VERSION 5.7 ;
  NOWIREEXTENSIONATPIN ON ;
  DIVIDERCHAR "/" ;
  BUSBITCHARS "[]" ;
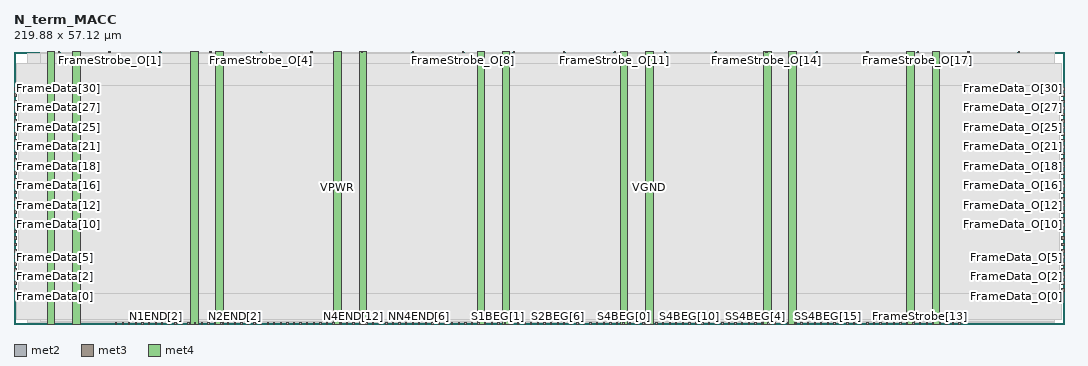
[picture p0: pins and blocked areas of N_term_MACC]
MACRO N_term_MACC
  CLASS BLOCK ;
  FOREIGN N_term_MACC ;
  ORIGIN 0.000 0.000 ;
  SIZE 219.880 BY 57.120 ;
  PIN CI
    DIRECTION INPUT ;
    USE SIGNAL ;
    PORT
      LAYER met2 ;
        RECT 98.530 0.000 98.810 0.280 ;
    END
  END CI
  PIN FrameData[0]
    DIRECTION INPUT ;
    USE SIGNAL ;
    ANTENNAGATEAREA 0.593700 ;
    ANTENNADIFFAREA 0.434700 ;
    PORT
      LAYER met3 ;
        RECT 0.000 6.840 0.600 7.440 ;
    END
  END FrameData[0]
  PIN FrameData[10]
    DIRECTION INPUT ;
    USE SIGNAL ;
    ANTENNAGATEAREA 0.593700 ;
    ANTENNADIFFAREA 0.434700 ;
    PORT
      LAYER met3 ;
        RECT 0.000 20.440 0.600 21.040 ;
    END
  END FrameData[10]
  PIN FrameData[11]
    DIRECTION INPUT ;
    USE SIGNAL ;
    ANTENNAGATEAREA 0.593700 ;
    ANTENNADIFFAREA 0.434700 ;
    PORT
      LAYER met3 ;
        RECT 0.000 21.800 0.600 22.400 ;
    END
  END FrameData[11]
  PIN FrameData[12]
    DIRECTION INPUT ;
    USE SIGNAL ;
    ANTENNAGATEAREA 0.159000 ;
    PORT
      LAYER met3 ;
        RECT 0.000 23.160 0.600 23.760 ;
    END
  END FrameData[12]
  PIN FrameData[13]
    DIRECTION INPUT ;
    USE SIGNAL ;
    ANTENNAGATEAREA 0.593700 ;
    ANTENNADIFFAREA 0.434700 ;
    PORT
      LAYER met3 ;
        RECT 0.000 24.520 0.600 25.120 ;
    END
  END FrameData[13]
  PIN FrameData[14]
    DIRECTION INPUT ;
    USE SIGNAL ;
    ANTENNAGATEAREA 0.593700 ;
    ANTENNADIFFAREA 0.434700 ;
    PORT
      LAYER met3 ;
        RECT 0.000 25.880 0.600 26.480 ;
    END
  END FrameData[14]
  PIN FrameData[15]
    DIRECTION INPUT ;
    USE SIGNAL ;
    ANTENNAGATEAREA 0.593700 ;
    ANTENNADIFFAREA 0.434700 ;
    PORT
      LAYER met3 ;
        RECT 0.000 27.240 0.600 27.840 ;
    END
  END FrameData[15]
  PIN FrameData[16]
    DIRECTION INPUT ;
    USE SIGNAL ;
    ANTENNAGATEAREA 0.593700 ;
    ANTENNADIFFAREA 0.434700 ;
    PORT
      LAYER met3 ;
        RECT 0.000 28.600 0.600 29.200 ;
    END
  END FrameData[16]
  PIN FrameData[17]
    DIRECTION INPUT ;
    USE SIGNAL ;
    ANTENNAGATEAREA 0.593700 ;
    ANTENNADIFFAREA 0.434700 ;
    PORT
      LAYER met3 ;
        RECT 0.000 29.960 0.600 30.560 ;
    END
  END FrameData[17]
  PIN FrameData[18]
    DIRECTION INPUT ;
    USE SIGNAL ;
    ANTENNAGATEAREA 0.593700 ;
    ANTENNADIFFAREA 0.434700 ;
    PORT
      LAYER met3 ;
        RECT 0.000 31.320 0.600 31.920 ;
    END
  END FrameData[18]
  PIN FrameData[19]
    DIRECTION INPUT ;
    USE SIGNAL ;
    ANTENNAGATEAREA 0.593700 ;
    ANTENNADIFFAREA 0.434700 ;
    PORT
      LAYER met3 ;
        RECT 0.000 32.680 0.600 33.280 ;
    END
  END FrameData[19]
  PIN FrameData[1]
    DIRECTION INPUT ;
    USE SIGNAL ;
    ANTENNAGATEAREA 0.159000 ;
    PORT
      LAYER met3 ;
        RECT 0.000 8.200 0.600 8.800 ;
    END
  END FrameData[1]
  PIN FrameData[20]
    DIRECTION INPUT ;
    USE SIGNAL ;
    ANTENNAGATEAREA 0.593700 ;
    ANTENNADIFFAREA 0.434700 ;
    PORT
      LAYER met3 ;
        RECT 0.000 34.040 0.600 34.640 ;
    END
  END FrameData[20]
  PIN FrameData[21]
    DIRECTION INPUT ;
    USE SIGNAL ;
    ANTENNAGATEAREA 0.593700 ;
    ANTENNADIFFAREA 0.434700 ;
    PORT
      LAYER met3 ;
        RECT 0.000 35.400 0.600 36.000 ;
    END
  END FrameData[21]
  PIN FrameData[22]
    DIRECTION INPUT ;
    USE SIGNAL ;
    ANTENNAGATEAREA 0.159000 ;
    PORT
      LAYER met3 ;
        RECT 0.000 36.760 0.600 37.360 ;
    END
  END FrameData[22]
  PIN FrameData[23]
    DIRECTION INPUT ;
    USE SIGNAL ;
    ANTENNAGATEAREA 0.593700 ;
    ANTENNADIFFAREA 0.434700 ;
    PORT
      LAYER met3 ;
        RECT 0.000 38.120 0.600 38.720 ;
    END
  END FrameData[23]
  PIN FrameData[24]
    DIRECTION INPUT ;
    USE SIGNAL ;
    ANTENNAGATEAREA 0.593700 ;
    ANTENNADIFFAREA 0.434700 ;
    PORT
      LAYER met3 ;
        RECT 0.000 39.480 0.600 40.080 ;
    END
  END FrameData[24]
  PIN FrameData[25]
    DIRECTION INPUT ;
    USE SIGNAL ;
    ANTENNAGATEAREA 0.593700 ;
    ANTENNADIFFAREA 0.434700 ;
    PORT
      LAYER met3 ;
        RECT 0.000 40.840 0.600 41.440 ;
    END
  END FrameData[25]
  PIN FrameData[26]
    DIRECTION INPUT ;
    USE SIGNAL ;
    ANTENNAGATEAREA 0.593700 ;
    ANTENNADIFFAREA 0.434700 ;
    PORT
      LAYER met3 ;
        RECT 0.000 42.200 0.600 42.800 ;
    END
  END FrameData[26]
  PIN FrameData[27]
    DIRECTION INPUT ;
    USE SIGNAL ;
    ANTENNAGATEAREA 0.593700 ;
    ANTENNADIFFAREA 0.434700 ;
    PORT
      LAYER met3 ;
        RECT 0.000 43.560 0.600 44.160 ;
    END
  END FrameData[27]
  PIN FrameData[28]
    DIRECTION INPUT ;
    USE SIGNAL ;
    ANTENNAGATEAREA 0.593700 ;
    ANTENNADIFFAREA 0.434700 ;
    PORT
      LAYER met3 ;
        RECT 0.000 44.920 0.600 45.520 ;
    END
  END FrameData[28]
  PIN FrameData[29]
    DIRECTION INPUT ;
    USE SIGNAL ;
    ANTENNAGATEAREA 0.593700 ;
    ANTENNADIFFAREA 0.434700 ;
    PORT
      LAYER met3 ;
        RECT 0.000 46.280 0.600 46.880 ;
    END
  END FrameData[29]
  PIN FrameData[2]
    DIRECTION INPUT ;
    USE SIGNAL ;
    ANTENNAGATEAREA 0.593700 ;
    ANTENNADIFFAREA 0.434700 ;
    PORT
      LAYER met3 ;
        RECT 0.000 9.560 0.600 10.160 ;
    END
  END FrameData[2]
  PIN FrameData[30]
    DIRECTION INPUT ;
    USE SIGNAL ;
    ANTENNAGATEAREA 0.593700 ;
    ANTENNADIFFAREA 0.434700 ;
    PORT
      LAYER met3 ;
        RECT 0.000 47.640 0.600 48.240 ;
    END
  END FrameData[30]
  PIN FrameData[31]
    DIRECTION INPUT ;
    USE SIGNAL ;
    ANTENNAGATEAREA 0.593700 ;
    ANTENNADIFFAREA 0.434700 ;
    PORT
      LAYER met3 ;
        RECT 0.000 49.000 0.600 49.600 ;
    END
  END FrameData[31]
  PIN FrameData[3]
    DIRECTION INPUT ;
    USE SIGNAL ;
    ANTENNAGATEAREA 0.593700 ;
    ANTENNADIFFAREA 0.434700 ;
    PORT
      LAYER met3 ;
        RECT 0.000 10.920 0.600 11.520 ;
    END
  END FrameData[3]
  PIN FrameData[4]
    DIRECTION INPUT ;
    USE SIGNAL ;
    ANTENNAGATEAREA 0.593700 ;
    ANTENNADIFFAREA 0.434700 ;
    PORT
      LAYER met3 ;
        RECT 0.000 12.280 0.600 12.880 ;
    END
  END FrameData[4]
  PIN FrameData[5]
    DIRECTION INPUT ;
    USE SIGNAL ;
    ANTENNAGATEAREA 0.593700 ;
    ANTENNADIFFAREA 0.434700 ;
    PORT
      LAYER met3 ;
        RECT 0.000 13.640 0.600 14.240 ;
    END
  END FrameData[5]
  PIN FrameData[6]
    DIRECTION INPUT ;
    USE SIGNAL ;
    ANTENNAGATEAREA 0.593700 ;
    ANTENNADIFFAREA 0.434700 ;
    PORT
      LAYER met3 ;
        RECT 0.000 15.000 0.600 15.600 ;
    END
  END FrameData[6]
  PIN FrameData[7]
    DIRECTION INPUT ;
    USE SIGNAL ;
    ANTENNAGATEAREA 0.593700 ;
    ANTENNADIFFAREA 0.434700 ;
    PORT
      LAYER met3 ;
        RECT 0.000 16.360 0.600 16.960 ;
    END
  END FrameData[7]
  PIN FrameData[8]
    DIRECTION INPUT ;
    USE SIGNAL ;
    ANTENNAGATEAREA 0.593700 ;
    ANTENNADIFFAREA 0.434700 ;
    PORT
      LAYER met3 ;
        RECT 0.000 17.720 0.600 18.320 ;
    END
  END FrameData[8]
  PIN FrameData[9]
    DIRECTION INPUT ;
    USE SIGNAL ;
    ANTENNAGATEAREA 0.593700 ;
    ANTENNADIFFAREA 0.434700 ;
    PORT
      LAYER met3 ;
        RECT 0.000 19.080 0.600 19.680 ;
    END
  END FrameData[9]
  PIN FrameData_O[0]
    DIRECTION OUTPUT ;
    USE SIGNAL ;
    ANTENNADIFFAREA 0.702900 ;
    PORT
      LAYER met3 ;
        RECT 219.280 6.840 219.880 7.440 ;
    END
  END FrameData_O[0]
  PIN FrameData_O[10]
    DIRECTION OUTPUT ;
    USE SIGNAL ;
    ANTENNADIFFAREA 0.702900 ;
    PORT
      LAYER met3 ;
        RECT 219.280 20.440 219.880 21.040 ;
    END
  END FrameData_O[10]
  PIN FrameData_O[11]
    DIRECTION OUTPUT ;
    USE SIGNAL ;
    ANTENNADIFFAREA 0.702900 ;
    PORT
      LAYER met3 ;
        RECT 219.280 21.800 219.880 22.400 ;
    END
  END FrameData_O[11]
  PIN FrameData_O[12]
    DIRECTION OUTPUT ;
    USE SIGNAL ;
    ANTENNADIFFAREA 0.702900 ;
    PORT
      LAYER met3 ;
        RECT 219.280 23.160 219.880 23.760 ;
    END
  END FrameData_O[12]
  PIN FrameData_O[13]
    DIRECTION OUTPUT ;
    USE SIGNAL ;
    ANTENNADIFFAREA 0.702900 ;
    PORT
      LAYER met3 ;
        RECT 219.280 24.520 219.880 25.120 ;
    END
  END FrameData_O[13]
  PIN FrameData_O[14]
    DIRECTION OUTPUT ;
    USE SIGNAL ;
    ANTENNADIFFAREA 0.702900 ;
    PORT
      LAYER met3 ;
        RECT 219.280 25.880 219.880 26.480 ;
    END
  END FrameData_O[14]
  PIN FrameData_O[15]
    DIRECTION OUTPUT ;
    USE SIGNAL ;
    ANTENNADIFFAREA 0.702900 ;
    PORT
      LAYER met3 ;
        RECT 219.280 27.240 219.880 27.840 ;
    END
  END FrameData_O[15]
  PIN FrameData_O[16]
    DIRECTION OUTPUT ;
    USE SIGNAL ;
    ANTENNADIFFAREA 0.702900 ;
    PORT
      LAYER met3 ;
        RECT 219.280 28.600 219.880 29.200 ;
    END
  END FrameData_O[16]
  PIN FrameData_O[17]
    DIRECTION OUTPUT ;
    USE SIGNAL ;
    ANTENNADIFFAREA 0.702900 ;
    PORT
      LAYER met3 ;
        RECT 219.280 29.960 219.880 30.560 ;
    END
  END FrameData_O[17]
  PIN FrameData_O[18]
    DIRECTION OUTPUT ;
    USE SIGNAL ;
    ANTENNADIFFAREA 0.702900 ;
    PORT
      LAYER met3 ;
        RECT 219.280 31.320 219.880 31.920 ;
    END
  END FrameData_O[18]
  PIN FrameData_O[19]
    DIRECTION OUTPUT ;
    USE SIGNAL ;
    ANTENNADIFFAREA 0.702900 ;
    PORT
      LAYER met3 ;
        RECT 219.280 32.680 219.880 33.280 ;
    END
  END FrameData_O[19]
  PIN FrameData_O[1]
    DIRECTION OUTPUT ;
    USE SIGNAL ;
    ANTENNADIFFAREA 0.702900 ;
    PORT
      LAYER met3 ;
        RECT 219.280 8.200 219.880 8.800 ;
    END
  END FrameData_O[1]
  PIN FrameData_O[20]
    DIRECTION OUTPUT ;
    USE SIGNAL ;
    ANTENNADIFFAREA 0.702900 ;
    PORT
      LAYER met3 ;
        RECT 219.280 34.040 219.880 34.640 ;
    END
  END FrameData_O[20]
  PIN FrameData_O[21]
    DIRECTION OUTPUT ;
    USE SIGNAL ;
    ANTENNADIFFAREA 0.702900 ;
    PORT
      LAYER met3 ;
        RECT 219.280 35.400 219.880 36.000 ;
    END
  END FrameData_O[21]
  PIN FrameData_O[22]
    DIRECTION OUTPUT ;
    USE SIGNAL ;
    ANTENNADIFFAREA 0.702900 ;
    PORT
      LAYER met3 ;
        RECT 219.280 36.760 219.880 37.360 ;
    END
  END FrameData_O[22]
  PIN FrameData_O[23]
    DIRECTION OUTPUT ;
    USE SIGNAL ;
    ANTENNADIFFAREA 0.702900 ;
    PORT
      LAYER met3 ;
        RECT 219.280 38.120 219.880 38.720 ;
    END
  END FrameData_O[23]
  PIN FrameData_O[24]
    DIRECTION OUTPUT ;
    USE SIGNAL ;
    ANTENNADIFFAREA 0.702900 ;
    PORT
      LAYER met3 ;
        RECT 219.280 39.480 219.880 40.080 ;
    END
  END FrameData_O[24]
  PIN FrameData_O[25]
    DIRECTION OUTPUT ;
    USE SIGNAL ;
    ANTENNADIFFAREA 0.702900 ;
    PORT
      LAYER met3 ;
        RECT 219.280 40.840 219.880 41.440 ;
    END
  END FrameData_O[25]
  PIN FrameData_O[26]
    DIRECTION OUTPUT ;
    USE SIGNAL ;
    ANTENNADIFFAREA 0.702900 ;
    PORT
      LAYER met3 ;
        RECT 219.280 42.200 219.880 42.800 ;
    END
  END FrameData_O[26]
  PIN FrameData_O[27]
    DIRECTION OUTPUT ;
    USE SIGNAL ;
    ANTENNADIFFAREA 0.702900 ;
    PORT
      LAYER met3 ;
        RECT 219.280 43.560 219.880 44.160 ;
    END
  END FrameData_O[27]
  PIN FrameData_O[28]
    DIRECTION OUTPUT ;
    USE SIGNAL ;
    ANTENNADIFFAREA 0.702900 ;
    PORT
      LAYER met3 ;
        RECT 219.280 44.920 219.880 45.520 ;
    END
  END FrameData_O[28]
  PIN FrameData_O[29]
    DIRECTION OUTPUT ;
    USE SIGNAL ;
    ANTENNADIFFAREA 0.702900 ;
    PORT
      LAYER met3 ;
        RECT 219.280 46.280 219.880 46.880 ;
    END
  END FrameData_O[29]
  PIN FrameData_O[2]
    DIRECTION OUTPUT ;
    USE SIGNAL ;
    ANTENNADIFFAREA 0.702900 ;
    PORT
      LAYER met3 ;
        RECT 219.280 9.560 219.880 10.160 ;
    END
  END FrameData_O[2]
  PIN FrameData_O[30]
    DIRECTION OUTPUT ;
    USE SIGNAL ;
    ANTENNADIFFAREA 0.702900 ;
    PORT
      LAYER met3 ;
        RECT 219.280 47.640 219.880 48.240 ;
    END
  END FrameData_O[30]
  PIN FrameData_O[31]
    DIRECTION OUTPUT ;
    USE SIGNAL ;
    ANTENNADIFFAREA 0.702900 ;
    PORT
      LAYER met3 ;
        RECT 219.280 49.000 219.880 49.600 ;
    END
  END FrameData_O[31]
  PIN FrameData_O[3]
    DIRECTION OUTPUT ;
    USE SIGNAL ;
    ANTENNADIFFAREA 0.702900 ;
    PORT
      LAYER met3 ;
        RECT 219.280 10.920 219.880 11.520 ;
    END
  END FrameData_O[3]
  PIN FrameData_O[4]
    DIRECTION OUTPUT ;
    USE SIGNAL ;
    ANTENNADIFFAREA 0.702900 ;
    PORT
      LAYER met3 ;
        RECT 219.280 12.280 219.880 12.880 ;
    END
  END FrameData_O[4]
  PIN FrameData_O[5]
    DIRECTION OUTPUT ;
    USE SIGNAL ;
    ANTENNADIFFAREA 0.702900 ;
    PORT
      LAYER met3 ;
        RECT 219.280 13.640 219.880 14.240 ;
    END
  END FrameData_O[5]
  PIN FrameData_O[6]
    DIRECTION OUTPUT ;
    USE SIGNAL ;
    ANTENNADIFFAREA 0.702900 ;
    PORT
      LAYER met3 ;
        RECT 219.280 15.000 219.880 15.600 ;
    END
  END FrameData_O[6]
  PIN FrameData_O[7]
    DIRECTION OUTPUT ;
    USE SIGNAL ;
    ANTENNADIFFAREA 0.702900 ;
    PORT
      LAYER met3 ;
        RECT 219.280 16.360 219.880 16.960 ;
    END
  END FrameData_O[7]
  PIN FrameData_O[8]
    DIRECTION OUTPUT ;
    USE SIGNAL ;
    ANTENNADIFFAREA 0.702900 ;
    PORT
      LAYER met3 ;
        RECT 219.280 17.720 219.880 18.320 ;
    END
  END FrameData_O[8]
  PIN FrameData_O[9]
    DIRECTION OUTPUT ;
    USE SIGNAL ;
    ANTENNADIFFAREA 0.702900 ;
    PORT
      LAYER met3 ;
        RECT 219.280 19.080 219.880 19.680 ;
    END
  END FrameData_O[9]
  PIN FrameStrobe[0]
    DIRECTION INPUT ;
    USE SIGNAL ;
    ANTENNAGATEAREA 0.159000 ;
    PORT
      LAYER met2 ;
        RECT 171.670 0.000 171.950 0.280 ;
    END
  END FrameStrobe[0]
  PIN FrameStrobe[10]
    DIRECTION INPUT ;
    USE SIGNAL ;
    ANTENNAGATEAREA 0.159000 ;
    PORT
      LAYER met2 ;
        RECT 185.470 0.000 185.750 0.280 ;
    END
  END FrameStrobe[10]
  PIN FrameStrobe[11]
    DIRECTION INPUT ;
    USE SIGNAL ;
    ANTENNAGATEAREA 0.159000 ;
    PORT
      LAYER met2 ;
        RECT 186.850 0.000 187.130 0.280 ;
    END
  END FrameStrobe[11]
  PIN FrameStrobe[12]
    DIRECTION INPUT ;
    USE SIGNAL ;
    ANTENNAGATEAREA 0.159000 ;
    PORT
      LAYER met2 ;
        RECT 188.230 0.000 188.510 0.280 ;
    END
  END FrameStrobe[12]
  PIN FrameStrobe[13]
    DIRECTION INPUT ;
    USE SIGNAL ;
    ANTENNAGATEAREA 0.159000 ;
    PORT
      LAYER met2 ;
        RECT 189.610 0.000 189.890 0.280 ;
    END
  END FrameStrobe[13]
  PIN FrameStrobe[14]
    DIRECTION INPUT ;
    USE SIGNAL ;
    ANTENNAGATEAREA 0.159000 ;
    PORT
      LAYER met2 ;
        RECT 190.990 0.000 191.270 0.280 ;
    END
  END FrameStrobe[14]
  PIN FrameStrobe[15]
    DIRECTION INPUT ;
    USE SIGNAL ;
    ANTENNAGATEAREA 0.159000 ;
    PORT
      LAYER met2 ;
        RECT 192.370 0.000 192.650 0.280 ;
    END
  END FrameStrobe[15]
  PIN FrameStrobe[16]
    DIRECTION INPUT ;
    USE SIGNAL ;
    ANTENNAGATEAREA 0.159000 ;
    PORT
      LAYER met2 ;
        RECT 193.750 0.000 194.030 0.280 ;
    END
  END FrameStrobe[16]
  PIN FrameStrobe[17]
    DIRECTION INPUT ;
    USE SIGNAL ;
    ANTENNAGATEAREA 0.159000 ;
    PORT
      LAYER met2 ;
        RECT 195.130 0.000 195.410 0.280 ;
    END
  END FrameStrobe[17]
  PIN FrameStrobe[18]
    DIRECTION INPUT ;
    USE SIGNAL ;
    ANTENNAGATEAREA 0.159000 ;
    PORT
      LAYER met2 ;
        RECT 196.510 0.000 196.790 0.280 ;
    END
  END FrameStrobe[18]
  PIN FrameStrobe[19]
    DIRECTION INPUT ;
    USE SIGNAL ;
    ANTENNAGATEAREA 0.159000 ;
    PORT
      LAYER met2 ;
        RECT 197.890 0.000 198.170 0.280 ;
    END
  END FrameStrobe[19]
  PIN FrameStrobe[1]
    DIRECTION INPUT ;
    USE SIGNAL ;
    ANTENNAGATEAREA 0.159000 ;
    PORT
      LAYER met2 ;
        RECT 173.050 0.000 173.330 0.280 ;
    END
  END FrameStrobe[1]
  PIN FrameStrobe[2]
    DIRECTION INPUT ;
    USE SIGNAL ;
    ANTENNAGATEAREA 0.159000 ;
    PORT
      LAYER met2 ;
        RECT 174.430 0.000 174.710 0.280 ;
    END
  END FrameStrobe[2]
  PIN FrameStrobe[3]
    DIRECTION INPUT ;
    USE SIGNAL ;
    ANTENNAGATEAREA 0.159000 ;
    PORT
      LAYER met2 ;
        RECT 175.810 0.000 176.090 0.280 ;
    END
  END FrameStrobe[3]
  PIN FrameStrobe[4]
    DIRECTION INPUT ;
    USE SIGNAL ;
    ANTENNAGATEAREA 0.159000 ;
    PORT
      LAYER met2 ;
        RECT 177.190 0.000 177.470 0.280 ;
    END
  END FrameStrobe[4]
  PIN FrameStrobe[5]
    DIRECTION INPUT ;
    USE SIGNAL ;
    ANTENNAGATEAREA 0.159000 ;
    PORT
      LAYER met2 ;
        RECT 178.570 0.000 178.850 0.280 ;
    END
  END FrameStrobe[5]
  PIN FrameStrobe[6]
    DIRECTION INPUT ;
    USE SIGNAL ;
    ANTENNAGATEAREA 0.159000 ;
    PORT
      LAYER met2 ;
        RECT 179.950 0.000 180.230 0.280 ;
    END
  END FrameStrobe[6]
  PIN FrameStrobe[7]
    DIRECTION INPUT ;
    USE SIGNAL ;
    ANTENNAGATEAREA 0.159000 ;
    PORT
      LAYER met2 ;
        RECT 181.330 0.000 181.610 0.280 ;
    END
  END FrameStrobe[7]
  PIN FrameStrobe[8]
    DIRECTION INPUT ;
    USE SIGNAL ;
    ANTENNAGATEAREA 0.159000 ;
    PORT
      LAYER met2 ;
        RECT 182.710 0.000 182.990 0.280 ;
    END
  END FrameStrobe[8]
  PIN FrameStrobe[9]
    DIRECTION INPUT ;
    USE SIGNAL ;
    ANTENNAGATEAREA 0.159000 ;
    PORT
      LAYER met2 ;
        RECT 184.090 0.000 184.370 0.280 ;
    END
  END FrameStrobe[9]
  PIN FrameStrobe_O[0]
    DIRECTION OUTPUT ;
    USE SIGNAL ;
    ANTENNADIFFAREA 0.702900 ;
    PORT
      LAYER met2 ;
        RECT 9.290 56.840 9.570 57.120 ;
    END
  END FrameStrobe_O[0]
  PIN FrameStrobe_O[10]
    DIRECTION OUTPUT ;
    USE SIGNAL ;
    ANTENNADIFFAREA 0.702900 ;
    PORT
      LAYER met2 ;
        RECT 115.090 56.840 115.370 57.120 ;
    END
  END FrameStrobe_O[10]
  PIN FrameStrobe_O[11]
    DIRECTION OUTPUT ;
    USE SIGNAL ;
    ANTENNADIFFAREA 0.702900 ;
    PORT
      LAYER met2 ;
        RECT 125.670 56.840 125.950 57.120 ;
    END
  END FrameStrobe_O[11]
  PIN FrameStrobe_O[12]
    DIRECTION OUTPUT ;
    USE SIGNAL ;
    ANTENNADIFFAREA 0.702900 ;
    PORT
      LAYER met2 ;
        RECT 136.250 56.840 136.530 57.120 ;
    END
  END FrameStrobe_O[12]
  PIN FrameStrobe_O[13]
    DIRECTION OUTPUT ;
    USE SIGNAL ;
    ANTENNADIFFAREA 0.702900 ;
    PORT
      LAYER met2 ;
        RECT 146.830 56.840 147.110 57.120 ;
    END
  END FrameStrobe_O[13]
  PIN FrameStrobe_O[14]
    DIRECTION OUTPUT ;
    USE SIGNAL ;
    ANTENNADIFFAREA 0.702900 ;
    PORT
      LAYER met2 ;
        RECT 157.410 56.840 157.690 57.120 ;
    END
  END FrameStrobe_O[14]
  PIN FrameStrobe_O[15]
    DIRECTION OUTPUT ;
    USE SIGNAL ;
    ANTENNADIFFAREA 0.702900 ;
    PORT
      LAYER met2 ;
        RECT 167.990 56.840 168.270 57.120 ;
    END
  END FrameStrobe_O[15]
  PIN FrameStrobe_O[16]
    DIRECTION OUTPUT ;
    USE SIGNAL ;
    ANTENNADIFFAREA 0.702900 ;
    PORT
      LAYER met2 ;
        RECT 178.570 56.840 178.850 57.120 ;
    END
  END FrameStrobe_O[16]
  PIN FrameStrobe_O[17]
    DIRECTION OUTPUT ;
    USE SIGNAL ;
    ANTENNADIFFAREA 0.702900 ;
    PORT
      LAYER met2 ;
        RECT 189.150 56.840 189.430 57.120 ;
    END
  END FrameStrobe_O[17]
  PIN FrameStrobe_O[18]
    DIRECTION OUTPUT ;
    USE SIGNAL ;
    ANTENNADIFFAREA 0.702900 ;
    PORT
      LAYER met2 ;
        RECT 199.730 56.840 200.010 57.120 ;
    END
  END FrameStrobe_O[18]
  PIN FrameStrobe_O[19]
    DIRECTION OUTPUT ;
    USE SIGNAL ;
    ANTENNADIFFAREA 0.702900 ;
    PORT
      LAYER met2 ;
        RECT 210.310 56.840 210.590 57.120 ;
    END
  END FrameStrobe_O[19]
  PIN FrameStrobe_O[1]
    DIRECTION OUTPUT ;
    USE SIGNAL ;
    ANTENNADIFFAREA 0.702900 ;
    PORT
      LAYER met2 ;
        RECT 19.870 56.840 20.150 57.120 ;
    END
  END FrameStrobe_O[1]
  PIN FrameStrobe_O[2]
    DIRECTION OUTPUT ;
    USE SIGNAL ;
    ANTENNADIFFAREA 0.702900 ;
    PORT
      LAYER met2 ;
        RECT 30.450 56.840 30.730 57.120 ;
    END
  END FrameStrobe_O[2]
  PIN FrameStrobe_O[3]
    DIRECTION OUTPUT ;
    USE SIGNAL ;
    ANTENNADIFFAREA 0.702900 ;
    PORT
      LAYER met2 ;
        RECT 41.030 56.840 41.310 57.120 ;
    END
  END FrameStrobe_O[3]
  PIN FrameStrobe_O[4]
    DIRECTION OUTPUT ;
    USE SIGNAL ;
    ANTENNADIFFAREA 0.702900 ;
    PORT
      LAYER met2 ;
        RECT 51.610 56.840 51.890 57.120 ;
    END
  END FrameStrobe_O[4]
  PIN FrameStrobe_O[5]
    DIRECTION OUTPUT ;
    USE SIGNAL ;
    ANTENNADIFFAREA 0.702900 ;
    PORT
      LAYER met2 ;
        RECT 62.190 56.840 62.470 57.120 ;
    END
  END FrameStrobe_O[5]
  PIN FrameStrobe_O[6]
    DIRECTION OUTPUT ;
    USE SIGNAL ;
    ANTENNADIFFAREA 0.702900 ;
    PORT
      LAYER met2 ;
        RECT 72.770 56.840 73.050 57.120 ;
    END
  END FrameStrobe_O[6]
  PIN FrameStrobe_O[7]
    DIRECTION OUTPUT ;
    USE SIGNAL ;
    ANTENNADIFFAREA 0.702900 ;
    PORT
      LAYER met2 ;
        RECT 83.350 56.840 83.630 57.120 ;
    END
  END FrameStrobe_O[7]
  PIN FrameStrobe_O[8]
    DIRECTION OUTPUT ;
    USE SIGNAL ;
    ANTENNADIFFAREA 0.702900 ;
    PORT
      LAYER met2 ;
        RECT 93.930 56.840 94.210 57.120 ;
    END
  END FrameStrobe_O[8]
  PIN FrameStrobe_O[9]
    DIRECTION OUTPUT ;
    USE SIGNAL ;
    ANTENNADIFFAREA 0.702900 ;
    PORT
      LAYER met2 ;
        RECT 104.510 56.840 104.790 57.120 ;
    END
  END FrameStrobe_O[9]
  PIN N1END[0]
    DIRECTION INPUT ;
    USE SIGNAL ;
    ANTENNAGATEAREA 0.159000 ;
    PORT
      LAYER met2 ;
        RECT 26.770 0.000 27.050 0.280 ;
    END
  END N1END[0]
  PIN N1END[1]
    DIRECTION INPUT ;
    USE SIGNAL ;
    ANTENNAGATEAREA 0.159000 ;
    PORT
      LAYER met2 ;
        RECT 28.150 0.000 28.430 0.280 ;
    END
  END N1END[1]
  PIN N1END[2]
    DIRECTION INPUT ;
    USE SIGNAL ;
    ANTENNAGATEAREA 0.159000 ;
    PORT
      LAYER met2 ;
        RECT 29.530 0.000 29.810 0.280 ;
    END
  END N1END[2]
  PIN N1END[3]
    DIRECTION INPUT ;
    USE SIGNAL ;
    ANTENNAGATEAREA 0.159000 ;
    PORT
      LAYER met2 ;
        RECT 30.910 0.000 31.190 0.280 ;
    END
  END N1END[3]
  PIN N2END[0]
    DIRECTION INPUT ;
    USE SIGNAL ;
    ANTENNAGATEAREA 0.159000 ;
    PORT
      LAYER met2 ;
        RECT 43.330 0.000 43.610 0.280 ;
    END
  END N2END[0]
  PIN N2END[1]
    DIRECTION INPUT ;
    USE SIGNAL ;
    ANTENNAGATEAREA 0.159000 ;
    PORT
      LAYER met2 ;
        RECT 44.710 0.000 44.990 0.280 ;
    END
  END N2END[1]
  PIN N2END[2]
    DIRECTION INPUT ;
    USE SIGNAL ;
    ANTENNAGATEAREA 0.159000 ;
    PORT
      LAYER met2 ;
        RECT 46.090 0.000 46.370 0.280 ;
    END
  END N2END[2]
  PIN N2END[3]
    DIRECTION INPUT ;
    USE SIGNAL ;
    ANTENNAGATEAREA 0.159000 ;
    PORT
      LAYER met2 ;
        RECT 47.470 0.000 47.750 0.280 ;
    END
  END N2END[3]
  PIN N2END[4]
    DIRECTION INPUT ;
    USE SIGNAL ;
    ANTENNAGATEAREA 0.159000 ;
    PORT
      LAYER met2 ;
        RECT 48.850 0.000 49.130 0.280 ;
    END
  END N2END[4]
  PIN N2END[5]
    DIRECTION INPUT ;
    USE SIGNAL ;
    ANTENNAGATEAREA 0.159000 ;
    PORT
      LAYER met2 ;
        RECT 50.230 0.000 50.510 0.280 ;
    END
  END N2END[5]
  PIN N2END[6]
    DIRECTION INPUT ;
    USE SIGNAL ;
    ANTENNAGATEAREA 0.159000 ;
    PORT
      LAYER met2 ;
        RECT 51.610 0.000 51.890 0.280 ;
    END
  END N2END[6]
  PIN N2END[7]
    DIRECTION INPUT ;
    USE SIGNAL ;
    ANTENNAGATEAREA 0.159000 ;
    PORT
      LAYER met2 ;
        RECT 52.990 0.000 53.270 0.280 ;
    END
  END N2END[7]
  PIN N2MID[0]
    DIRECTION INPUT ;
    USE SIGNAL ;
    ANTENNAGATEAREA 0.159000 ;
    PORT
      LAYER met2 ;
        RECT 32.290 0.000 32.570 0.280 ;
    END
  END N2MID[0]
  PIN N2MID[1]
    DIRECTION INPUT ;
    USE SIGNAL ;
    ANTENNAGATEAREA 0.159000 ;
    PORT
      LAYER met2 ;
        RECT 33.670 0.000 33.950 0.280 ;
    END
  END N2MID[1]
  PIN N2MID[2]
    DIRECTION INPUT ;
    USE SIGNAL ;
    ANTENNAGATEAREA 0.159000 ;
    PORT
      LAYER met2 ;
        RECT 35.050 0.000 35.330 0.280 ;
    END
  END N2MID[2]
  PIN N2MID[3]
    DIRECTION INPUT ;
    USE SIGNAL ;
    ANTENNAGATEAREA 0.159000 ;
    PORT
      LAYER met2 ;
        RECT 36.430 0.000 36.710 0.280 ;
    END
  END N2MID[3]
  PIN N2MID[4]
    DIRECTION INPUT ;
    USE SIGNAL ;
    ANTENNAGATEAREA 0.159000 ;
    PORT
      LAYER met2 ;
        RECT 37.810 0.000 38.090 0.280 ;
    END
  END N2MID[4]
  PIN N2MID[5]
    DIRECTION INPUT ;
    USE SIGNAL ;
    ANTENNAGATEAREA 0.159000 ;
    PORT
      LAYER met2 ;
        RECT 39.190 0.000 39.470 0.280 ;
    END
  END N2MID[5]
  PIN N2MID[6]
    DIRECTION INPUT ;
    USE SIGNAL ;
    ANTENNAGATEAREA 0.159000 ;
    PORT
      LAYER met2 ;
        RECT 40.570 0.000 40.850 0.280 ;
    END
  END N2MID[6]
  PIN N2MID[7]
    DIRECTION INPUT ;
    USE SIGNAL ;
    ANTENNAGATEAREA 0.159000 ;
    PORT
      LAYER met2 ;
        RECT 41.950 0.000 42.230 0.280 ;
    END
  END N2MID[7]
  PIN N4END[0]
    DIRECTION INPUT ;
    USE SIGNAL ;
    ANTENNAGATEAREA 0.159000 ;
    PORT
      LAYER met2 ;
        RECT 54.370 0.000 54.650 0.280 ;
    END
  END N4END[0]
  PIN N4END[10]
    DIRECTION INPUT ;
    USE SIGNAL ;
    ANTENNAGATEAREA 0.159000 ;
    PORT
      LAYER met2 ;
        RECT 68.170 0.000 68.450 0.280 ;
    END
  END N4END[10]
  PIN N4END[11]
    DIRECTION INPUT ;
    USE SIGNAL ;
    ANTENNAGATEAREA 0.159000 ;
    PORT
      LAYER met2 ;
        RECT 69.550 0.000 69.830 0.280 ;
    END
  END N4END[11]
  PIN N4END[12]
    DIRECTION INPUT ;
    USE SIGNAL ;
    ANTENNAGATEAREA 0.159000 ;
    PORT
      LAYER met2 ;
        RECT 70.930 0.000 71.210 0.280 ;
    END
  END N4END[12]
  PIN N4END[13]
    DIRECTION INPUT ;
    USE SIGNAL ;
    ANTENNAGATEAREA 0.159000 ;
    PORT
      LAYER met2 ;
        RECT 72.310 0.000 72.590 0.280 ;
    END
  END N4END[13]
  PIN N4END[14]
    DIRECTION INPUT ;
    USE SIGNAL ;
    ANTENNAGATEAREA 0.159000 ;
    PORT
      LAYER met2 ;
        RECT 73.690 0.000 73.970 0.280 ;
    END
  END N4END[14]
  PIN N4END[15]
    DIRECTION INPUT ;
    USE SIGNAL ;
    ANTENNAGATEAREA 0.159000 ;
    PORT
      LAYER met2 ;
        RECT 75.070 0.000 75.350 0.280 ;
    END
  END N4END[15]
  PIN N4END[1]
    DIRECTION INPUT ;
    USE SIGNAL ;
    ANTENNAGATEAREA 0.159000 ;
    PORT
      LAYER met2 ;
        RECT 55.750 0.000 56.030 0.280 ;
    END
  END N4END[1]
  PIN N4END[2]
    DIRECTION INPUT ;
    USE SIGNAL ;
    ANTENNAGATEAREA 0.159000 ;
    PORT
      LAYER met2 ;
        RECT 57.130 0.000 57.410 0.280 ;
    END
  END N4END[2]
  PIN N4END[3]
    DIRECTION INPUT ;
    USE SIGNAL ;
    ANTENNAGATEAREA 0.159000 ;
    PORT
      LAYER met2 ;
        RECT 58.510 0.000 58.790 0.280 ;
    END
  END N4END[3]
  PIN N4END[4]
    DIRECTION INPUT ;
    USE SIGNAL ;
    ANTENNAGATEAREA 0.159000 ;
    PORT
      LAYER met2 ;
        RECT 59.890 0.000 60.170 0.280 ;
    END
  END N4END[4]
  PIN N4END[5]
    DIRECTION INPUT ;
    USE SIGNAL ;
    ANTENNAGATEAREA 0.159000 ;
    PORT
      LAYER met2 ;
        RECT 61.270 0.000 61.550 0.280 ;
    END
  END N4END[5]
  PIN N4END[6]
    DIRECTION INPUT ;
    USE SIGNAL ;
    ANTENNAGATEAREA 0.159000 ;
    PORT
      LAYER met2 ;
        RECT 62.650 0.000 62.930 0.280 ;
    END
  END N4END[6]
  PIN N4END[7]
    DIRECTION INPUT ;
    USE SIGNAL ;
    ANTENNAGATEAREA 0.159000 ;
    PORT
      LAYER met2 ;
        RECT 64.030 0.000 64.310 0.280 ;
    END
  END N4END[7]
  PIN N4END[8]
    DIRECTION INPUT ;
    USE SIGNAL ;
    ANTENNAGATEAREA 0.159000 ;
    PORT
      LAYER met2 ;
        RECT 65.410 0.000 65.690 0.280 ;
    END
  END N4END[8]
  PIN N4END[9]
    DIRECTION INPUT ;
    USE SIGNAL ;
    ANTENNAGATEAREA 0.159000 ;
    PORT
      LAYER met2 ;
        RECT 66.790 0.000 67.070 0.280 ;
    END
  END N4END[9]
  PIN NN4END[0]
    DIRECTION INPUT ;
    USE SIGNAL ;
    ANTENNAGATEAREA 0.159000 ;
    PORT
      LAYER met2 ;
        RECT 76.450 0.000 76.730 0.280 ;
    END
  END NN4END[0]
  PIN NN4END[10]
    DIRECTION INPUT ;
    USE SIGNAL ;
    ANTENNAGATEAREA 0.159000 ;
    PORT
      LAYER met2 ;
        RECT 90.250 0.000 90.530 0.280 ;
    END
  END NN4END[10]
  PIN NN4END[11]
    DIRECTION INPUT ;
    USE SIGNAL ;
    ANTENNAGATEAREA 0.159000 ;
    PORT
      LAYER met2 ;
        RECT 91.630 0.000 91.910 0.280 ;
    END
  END NN4END[11]
  PIN NN4END[12]
    DIRECTION INPUT ;
    USE SIGNAL ;
    ANTENNAGATEAREA 0.159000 ;
    PORT
      LAYER met2 ;
        RECT 93.010 0.000 93.290 0.280 ;
    END
  END NN4END[12]
  PIN NN4END[13]
    DIRECTION INPUT ;
    USE SIGNAL ;
    ANTENNAGATEAREA 0.159000 ;
    PORT
      LAYER met2 ;
        RECT 94.390 0.000 94.670 0.280 ;
    END
  END NN4END[13]
  PIN NN4END[14]
    DIRECTION INPUT ;
    USE SIGNAL ;
    ANTENNAGATEAREA 0.159000 ;
    PORT
      LAYER met2 ;
        RECT 95.770 0.000 96.050 0.280 ;
    END
  END NN4END[14]
  PIN NN4END[15]
    DIRECTION INPUT ;
    USE SIGNAL ;
    ANTENNAGATEAREA 0.159000 ;
    PORT
      LAYER met2 ;
        RECT 97.150 0.000 97.430 0.280 ;
    END
  END NN4END[15]
  PIN NN4END[1]
    DIRECTION INPUT ;
    USE SIGNAL ;
    ANTENNAGATEAREA 0.159000 ;
    PORT
      LAYER met2 ;
        RECT 77.830 0.000 78.110 0.280 ;
    END
  END NN4END[1]
  PIN NN4END[2]
    DIRECTION INPUT ;
    USE SIGNAL ;
    ANTENNAGATEAREA 0.159000 ;
    PORT
      LAYER met2 ;
        RECT 79.210 0.000 79.490 0.280 ;
    END
  END NN4END[2]
  PIN NN4END[3]
    DIRECTION INPUT ;
    USE SIGNAL ;
    ANTENNAGATEAREA 0.159000 ;
    PORT
      LAYER met2 ;
        RECT 80.590 0.000 80.870 0.280 ;
    END
  END NN4END[3]
  PIN NN4END[4]
    DIRECTION INPUT ;
    USE SIGNAL ;
    ANTENNAGATEAREA 0.159000 ;
    PORT
      LAYER met2 ;
        RECT 81.970 0.000 82.250 0.280 ;
    END
  END NN4END[4]
  PIN NN4END[5]
    DIRECTION INPUT ;
    USE SIGNAL ;
    ANTENNAGATEAREA 0.159000 ;
    PORT
      LAYER met2 ;
        RECT 83.350 0.000 83.630 0.280 ;
    END
  END NN4END[5]
  PIN NN4END[6]
    DIRECTION INPUT ;
    USE SIGNAL ;
    ANTENNAGATEAREA 0.159000 ;
    PORT
      LAYER met2 ;
        RECT 84.730 0.000 85.010 0.280 ;
    END
  END NN4END[6]
  PIN NN4END[7]
    DIRECTION INPUT ;
    USE SIGNAL ;
    ANTENNAGATEAREA 0.159000 ;
    PORT
      LAYER met2 ;
        RECT 86.110 0.000 86.390 0.280 ;
    END
  END NN4END[7]
  PIN NN4END[8]
    DIRECTION INPUT ;
    USE SIGNAL ;
    ANTENNAGATEAREA 0.593700 ;
    ANTENNADIFFAREA 0.434700 ;
    PORT
      LAYER met2 ;
        RECT 87.490 0.000 87.770 0.280 ;
    END
  END NN4END[8]
  PIN NN4END[9]
    DIRECTION INPUT ;
    USE SIGNAL ;
    ANTENNAGATEAREA 0.159000 ;
    PORT
      LAYER met2 ;
        RECT 88.870 0.000 89.150 0.280 ;
    END
  END NN4END[9]
  PIN N_GBUF_END[0]
    DIRECTION INPUT ;
    USE SIGNAL ;
    PORT
      LAYER met2 ;
        RECT 21.250 0.000 21.530 0.280 ;
    END
  END N_GBUF_END[0]
  PIN N_GBUF_END[1]
    DIRECTION INPUT ;
    USE SIGNAL ;
    PORT
      LAYER met2 ;
        RECT 22.630 0.000 22.910 0.280 ;
    END
  END N_GBUF_END[1]
  PIN N_GBUF_END[2]
    DIRECTION INPUT ;
    USE SIGNAL ;
    PORT
      LAYER met2 ;
        RECT 24.010 0.000 24.290 0.280 ;
    END
  END N_GBUF_END[2]
  PIN N_GBUF_END[3]
    DIRECTION INPUT ;
    USE SIGNAL ;
    PORT
      LAYER met2 ;
        RECT 25.390 0.000 25.670 0.280 ;
    END
  END N_GBUF_END[3]
  PIN S1BEG[0]
    DIRECTION OUTPUT ;
    USE SIGNAL ;
    ANTENNADIFFAREA 0.702900 ;
    PORT
      LAYER met2 ;
        RECT 99.910 0.000 100.190 0.280 ;
    END
  END S1BEG[0]
  PIN S1BEG[1]
    DIRECTION OUTPUT ;
    USE SIGNAL ;
    ANTENNADIFFAREA 0.702900 ;
    PORT
      LAYER met2 ;
        RECT 101.290 0.000 101.570 0.280 ;
    END
  END S1BEG[1]
  PIN S1BEG[2]
    DIRECTION OUTPUT ;
    USE SIGNAL ;
    ANTENNADIFFAREA 0.702900 ;
    PORT
      LAYER met2 ;
        RECT 102.670 0.000 102.950 0.280 ;
    END
  END S1BEG[2]
  PIN S1BEG[3]
    DIRECTION OUTPUT ;
    USE SIGNAL ;
    ANTENNADIFFAREA 0.702900 ;
    PORT
      LAYER met2 ;
        RECT 104.050 0.000 104.330 0.280 ;
    END
  END S1BEG[3]
  PIN S2BEG[0]
    DIRECTION OUTPUT ;
    USE SIGNAL ;
    ANTENNADIFFAREA 0.702900 ;
    PORT
      LAYER met2 ;
        RECT 105.430 0.000 105.710 0.280 ;
    END
  END S2BEG[0]
  PIN S2BEG[1]
    DIRECTION OUTPUT ;
    USE SIGNAL ;
    ANTENNADIFFAREA 0.702900 ;
    PORT
      LAYER met2 ;
        RECT 106.810 0.000 107.090 0.280 ;
    END
  END S2BEG[1]
  PIN S2BEG[2]
    DIRECTION OUTPUT ;
    USE SIGNAL ;
    ANTENNADIFFAREA 0.702900 ;
    PORT
      LAYER met2 ;
        RECT 108.190 0.000 108.470 0.280 ;
    END
  END S2BEG[2]
  PIN S2BEG[3]
    DIRECTION OUTPUT ;
    USE SIGNAL ;
    ANTENNADIFFAREA 0.702900 ;
    PORT
      LAYER met2 ;
        RECT 109.570 0.000 109.850 0.280 ;
    END
  END S2BEG[3]
  PIN S2BEG[4]
    DIRECTION OUTPUT ;
    USE SIGNAL ;
    ANTENNADIFFAREA 0.702900 ;
    PORT
      LAYER met2 ;
        RECT 110.950 0.000 111.230 0.280 ;
    END
  END S2BEG[4]
  PIN S2BEG[5]
    DIRECTION OUTPUT ;
    USE SIGNAL ;
    ANTENNADIFFAREA 0.702900 ;
    PORT
      LAYER met2 ;
        RECT 112.330 0.000 112.610 0.280 ;
    END
  END S2BEG[5]
  PIN S2BEG[6]
    DIRECTION OUTPUT ;
    USE SIGNAL ;
    ANTENNADIFFAREA 0.702900 ;
    PORT
      LAYER met2 ;
        RECT 113.710 0.000 113.990 0.280 ;
    END
  END S2BEG[6]
  PIN S2BEG[7]
    DIRECTION OUTPUT ;
    USE SIGNAL ;
    ANTENNADIFFAREA 0.702900 ;
    PORT
      LAYER met2 ;
        RECT 115.090 0.000 115.370 0.280 ;
    END
  END S2BEG[7]
  PIN S2BEGb[0]
    DIRECTION OUTPUT ;
    USE SIGNAL ;
    ANTENNADIFFAREA 0.702900 ;
    PORT
      LAYER met2 ;
        RECT 116.470 0.000 116.750 0.280 ;
    END
  END S2BEGb[0]
  PIN S2BEGb[1]
    DIRECTION OUTPUT ;
    USE SIGNAL ;
    ANTENNADIFFAREA 0.702900 ;
    PORT
      LAYER met2 ;
        RECT 117.850 0.000 118.130 0.280 ;
    END
  END S2BEGb[1]
  PIN S2BEGb[2]
    DIRECTION OUTPUT ;
    USE SIGNAL ;
    ANTENNADIFFAREA 0.702900 ;
    PORT
      LAYER met2 ;
        RECT 119.230 0.000 119.510 0.280 ;
    END
  END S2BEGb[2]
  PIN S2BEGb[3]
    DIRECTION OUTPUT ;
    USE SIGNAL ;
    ANTENNADIFFAREA 0.702900 ;
    PORT
      LAYER met2 ;
        RECT 120.610 0.000 120.890 0.280 ;
    END
  END S2BEGb[3]
  PIN S2BEGb[4]
    DIRECTION OUTPUT ;
    USE SIGNAL ;
    ANTENNADIFFAREA 0.702900 ;
    PORT
      LAYER met2 ;
        RECT 121.990 0.000 122.270 0.280 ;
    END
  END S2BEGb[4]
  PIN S2BEGb[5]
    DIRECTION OUTPUT ;
    USE SIGNAL ;
    ANTENNADIFFAREA 0.702900 ;
    PORT
      LAYER met2 ;
        RECT 123.370 0.000 123.650 0.280 ;
    END
  END S2BEGb[5]
  PIN S2BEGb[6]
    DIRECTION OUTPUT ;
    USE SIGNAL ;
    ANTENNADIFFAREA 0.702900 ;
    PORT
      LAYER met2 ;
        RECT 124.750 0.000 125.030 0.280 ;
    END
  END S2BEGb[6]
  PIN S2BEGb[7]
    DIRECTION OUTPUT ;
    USE SIGNAL ;
    ANTENNADIFFAREA 0.702900 ;
    PORT
      LAYER met2 ;
        RECT 126.130 0.000 126.410 0.280 ;
    END
  END S2BEGb[7]
  PIN S4BEG[0]
    DIRECTION OUTPUT ;
    USE SIGNAL ;
    ANTENNADIFFAREA 0.702900 ;
    PORT
      LAYER met2 ;
        RECT 127.510 0.000 127.790 0.280 ;
    END
  END S4BEG[0]
  PIN S4BEG[10]
    DIRECTION OUTPUT ;
    USE SIGNAL ;
    ANTENNADIFFAREA 0.702900 ;
    PORT
      LAYER met2 ;
        RECT 141.310 0.000 141.590 0.280 ;
    END
  END S4BEG[10]
  PIN S4BEG[11]
    DIRECTION OUTPUT ;
    USE SIGNAL ;
    ANTENNADIFFAREA 0.702900 ;
    PORT
      LAYER met2 ;
        RECT 142.690 0.000 142.970 0.280 ;
    END
  END S4BEG[11]
  PIN S4BEG[12]
    DIRECTION OUTPUT ;
    USE SIGNAL ;
    ANTENNADIFFAREA 0.702900 ;
    PORT
      LAYER met2 ;
        RECT 144.070 0.000 144.350 0.280 ;
    END
  END S4BEG[12]
  PIN S4BEG[13]
    DIRECTION OUTPUT ;
    USE SIGNAL ;
    ANTENNADIFFAREA 0.702900 ;
    PORT
      LAYER met2 ;
        RECT 145.450 0.000 145.730 0.280 ;
    END
  END S4BEG[13]
  PIN S4BEG[14]
    DIRECTION OUTPUT ;
    USE SIGNAL ;
    ANTENNADIFFAREA 0.702900 ;
    PORT
      LAYER met2 ;
        RECT 146.830 0.000 147.110 0.280 ;
    END
  END S4BEG[14]
  PIN S4BEG[15]
    DIRECTION OUTPUT ;
    USE SIGNAL ;
    ANTENNADIFFAREA 0.702900 ;
    PORT
      LAYER met2 ;
        RECT 148.210 0.000 148.490 0.280 ;
    END
  END S4BEG[15]
  PIN S4BEG[1]
    DIRECTION OUTPUT ;
    USE SIGNAL ;
    ANTENNADIFFAREA 0.702900 ;
    PORT
      LAYER met2 ;
        RECT 128.890 0.000 129.170 0.280 ;
    END
  END S4BEG[1]
  PIN S4BEG[2]
    DIRECTION OUTPUT ;
    USE SIGNAL ;
    ANTENNADIFFAREA 0.702900 ;
    PORT
      LAYER met2 ;
        RECT 130.270 0.000 130.550 0.280 ;
    END
  END S4BEG[2]
  PIN S4BEG[3]
    DIRECTION OUTPUT ;
    USE SIGNAL ;
    ANTENNADIFFAREA 0.702900 ;
    PORT
      LAYER met2 ;
        RECT 131.650 0.000 131.930 0.280 ;
    END
  END S4BEG[3]
  PIN S4BEG[4]
    DIRECTION OUTPUT ;
    USE SIGNAL ;
    ANTENNADIFFAREA 0.702900 ;
    PORT
      LAYER met2 ;
        RECT 133.030 0.000 133.310 0.280 ;
    END
  END S4BEG[4]
  PIN S4BEG[5]
    DIRECTION OUTPUT ;
    USE SIGNAL ;
    ANTENNADIFFAREA 0.702900 ;
    PORT
      LAYER met2 ;
        RECT 134.410 0.000 134.690 0.280 ;
    END
  END S4BEG[5]
  PIN S4BEG[6]
    DIRECTION OUTPUT ;
    USE SIGNAL ;
    ANTENNADIFFAREA 0.702900 ;
    PORT
      LAYER met2 ;
        RECT 135.790 0.000 136.070 0.280 ;
    END
  END S4BEG[6]
  PIN S4BEG[7]
    DIRECTION OUTPUT ;
    USE SIGNAL ;
    ANTENNADIFFAREA 0.702900 ;
    PORT
      LAYER met2 ;
        RECT 137.170 0.000 137.450 0.280 ;
    END
  END S4BEG[7]
  PIN S4BEG[8]
    DIRECTION OUTPUT ;
    USE SIGNAL ;
    ANTENNADIFFAREA 0.702900 ;
    PORT
      LAYER met2 ;
        RECT 138.550 0.000 138.830 0.280 ;
    END
  END S4BEG[8]
  PIN S4BEG[9]
    DIRECTION OUTPUT ;
    USE SIGNAL ;
    ANTENNADIFFAREA 0.702900 ;
    PORT
      LAYER met2 ;
        RECT 139.930 0.000 140.210 0.280 ;
    END
  END S4BEG[9]
  PIN SS4BEG[0]
    DIRECTION OUTPUT ;
    USE SIGNAL ;
    ANTENNADIFFAREA 0.702900 ;
    PORT
      LAYER met2 ;
        RECT 149.590 0.000 149.870 0.280 ;
    END
  END SS4BEG[0]
  PIN SS4BEG[10]
    DIRECTION OUTPUT ;
    USE SIGNAL ;
    ANTENNADIFFAREA 0.702900 ;
    PORT
      LAYER met2 ;
        RECT 163.390 0.000 163.670 0.280 ;
    END
  END SS4BEG[10]
  PIN SS4BEG[11]
    DIRECTION OUTPUT ;
    USE SIGNAL ;
    ANTENNADIFFAREA 0.702900 ;
    PORT
      LAYER met2 ;
        RECT 164.770 0.000 165.050 0.280 ;
    END
  END SS4BEG[11]
  PIN SS4BEG[12]
    DIRECTION OUTPUT ;
    USE SIGNAL ;
    ANTENNADIFFAREA 0.702900 ;
    PORT
      LAYER met2 ;
        RECT 166.150 0.000 166.430 0.280 ;
    END
  END SS4BEG[12]
  PIN SS4BEG[13]
    DIRECTION OUTPUT ;
    USE SIGNAL ;
    ANTENNADIFFAREA 0.702900 ;
    PORT
      LAYER met2 ;
        RECT 167.530 0.000 167.810 0.280 ;
    END
  END SS4BEG[13]
  PIN SS4BEG[14]
    DIRECTION OUTPUT ;
    USE SIGNAL ;
    ANTENNADIFFAREA 0.702900 ;
    PORT
      LAYER met2 ;
        RECT 168.910 0.000 169.190 0.280 ;
    END
  END SS4BEG[14]
  PIN SS4BEG[15]
    DIRECTION OUTPUT ;
    USE SIGNAL ;
    ANTENNADIFFAREA 0.702900 ;
    PORT
      LAYER met2 ;
        RECT 170.290 0.000 170.570 0.280 ;
    END
  END SS4BEG[15]
  PIN SS4BEG[1]
    DIRECTION OUTPUT ;
    USE SIGNAL ;
    ANTENNADIFFAREA 0.702900 ;
    PORT
      LAYER met2 ;
        RECT 150.970 0.000 151.250 0.280 ;
    END
  END SS4BEG[1]
  PIN SS4BEG[2]
    DIRECTION OUTPUT ;
    USE SIGNAL ;
    ANTENNADIFFAREA 0.702900 ;
    PORT
      LAYER met2 ;
        RECT 152.350 0.000 152.630 0.280 ;
    END
  END SS4BEG[2]
  PIN SS4BEG[3]
    DIRECTION OUTPUT ;
    USE SIGNAL ;
    ANTENNADIFFAREA 0.702900 ;
    PORT
      LAYER met2 ;
        RECT 153.730 0.000 154.010 0.280 ;
    END
  END SS4BEG[3]
  PIN SS4BEG[4]
    DIRECTION OUTPUT ;
    USE SIGNAL ;
    ANTENNADIFFAREA 0.702900 ;
    PORT
      LAYER met2 ;
        RECT 155.110 0.000 155.390 0.280 ;
    END
  END SS4BEG[4]
  PIN SS4BEG[5]
    DIRECTION OUTPUT ;
    USE SIGNAL ;
    ANTENNADIFFAREA 0.702900 ;
    PORT
      LAYER met2 ;
        RECT 156.490 0.000 156.770 0.280 ;
    END
  END SS4BEG[5]
  PIN SS4BEG[6]
    DIRECTION OUTPUT ;
    USE SIGNAL ;
    ANTENNADIFFAREA 0.702900 ;
    PORT
      LAYER met2 ;
        RECT 157.870 0.000 158.150 0.280 ;
    END
  END SS4BEG[6]
  PIN SS4BEG[7]
    DIRECTION OUTPUT ;
    USE SIGNAL ;
    ANTENNADIFFAREA 0.702900 ;
    PORT
      LAYER met2 ;
        RECT 159.250 0.000 159.530 0.280 ;
    END
  END SS4BEG[7]
  PIN SS4BEG[8]
    DIRECTION OUTPUT ;
    USE SIGNAL ;
    ANTENNADIFFAREA 0.702900 ;
    PORT
      LAYER met2 ;
        RECT 160.630 0.000 160.910 0.280 ;
    END
  END SS4BEG[8]
  PIN SS4BEG[9]
    DIRECTION OUTPUT ;
    USE SIGNAL ;
    ANTENNADIFFAREA 0.702900 ;
    PORT
      LAYER met2 ;
        RECT 162.010 0.000 162.290 0.280 ;
    END
  END SS4BEG[9]
  PIN VGND
    DIRECTION INOUT ;
    USE GROUND ;
    PORT
      LAYER met4 ;
        RECT 12.260 0.000 13.860 57.120 ;
    END
    PORT
      LAYER met4 ;
        RECT 42.260 0.000 43.860 57.120 ;
    END
    PORT
      LAYER met4 ;
        RECT 72.260 0.000 73.860 57.120 ;
    END
    PORT
      LAYER met4 ;
        RECT 102.260 0.000 103.860 57.120 ;
    END
    PORT
      LAYER met4 ;
        RECT 132.260 0.000 133.860 57.120 ;
    END
    PORT
      LAYER met4 ;
        RECT 162.260 0.000 163.860 57.120 ;
    END
    PORT
      LAYER met4 ;
        RECT 192.260 0.000 193.860 57.120 ;
    END
  END VGND
  PIN VPWR
    DIRECTION INOUT ;
    USE POWER ;
    PORT
      LAYER met4 ;
        RECT 6.960 0.000 8.560 57.120 ;
    END
    PORT
      LAYER met4 ;
        RECT 36.960 0.000 38.560 57.120 ;
    END
    PORT
      LAYER met4 ;
        RECT 66.960 0.000 68.560 57.120 ;
    END
    PORT
      LAYER met4 ;
        RECT 96.960 0.000 98.560 57.120 ;
    END
    PORT
      LAYER met4 ;
        RECT 126.960 0.000 128.560 57.120 ;
    END
    PORT
      LAYER met4 ;
        RECT 156.960 0.000 158.560 57.120 ;
    END
    PORT
      LAYER met4 ;
        RECT 186.960 0.000 188.560 57.120 ;
    END
  END VPWR
  OBS
      LAYER nwell ;
        RECT 2.570 2.635 217.310 54.590 ;
      LAYER li1 ;
        RECT 2.760 2.635 217.120 54.485 ;
      LAYER met1 ;
        RECT 2.760 0.380 217.970 56.740 ;
      LAYER met2 ;
        RECT 5.610 56.560 9.010 56.850 ;
        RECT 9.850 56.560 19.590 56.850 ;
        RECT 20.430 56.560 30.170 56.850 ;
        RECT 31.010 56.560 40.750 56.850 ;
        RECT 41.590 56.560 51.330 56.850 ;
        RECT 52.170 56.560 61.910 56.850 ;
        RECT 62.750 56.560 72.490 56.850 ;
        RECT 73.330 56.560 83.070 56.850 ;
        RECT 83.910 56.560 93.650 56.850 ;
        RECT 94.490 56.560 104.230 56.850 ;
        RECT 105.070 56.560 114.810 56.850 ;
        RECT 115.650 56.560 125.390 56.850 ;
        RECT 126.230 56.560 135.970 56.850 ;
        RECT 136.810 56.560 146.550 56.850 ;
        RECT 147.390 56.560 157.130 56.850 ;
        RECT 157.970 56.560 167.710 56.850 ;
        RECT 168.550 56.560 178.290 56.850 ;
        RECT 179.130 56.560 188.870 56.850 ;
        RECT 189.710 56.560 199.450 56.850 ;
        RECT 200.290 56.560 210.030 56.850 ;
        RECT 210.870 56.560 217.950 56.850 ;
        RECT 5.610 0.560 217.950 56.560 ;
        RECT 5.610 0.270 20.970 0.560 ;
        RECT 21.810 0.270 22.350 0.560 ;
        RECT 23.190 0.270 23.730 0.560 ;
        RECT 24.570 0.270 25.110 0.560 ;
        RECT 25.950 0.270 26.490 0.560 ;
        RECT 27.330 0.270 27.870 0.560 ;
        RECT 28.710 0.270 29.250 0.560 ;
        RECT 30.090 0.270 30.630 0.560 ;
        RECT 31.470 0.270 32.010 0.560 ;
        RECT 32.850 0.270 33.390 0.560 ;
        RECT 34.230 0.270 34.770 0.560 ;
        RECT 35.610 0.270 36.150 0.560 ;
        RECT 36.990 0.270 37.530 0.560 ;
        RECT 38.370 0.270 38.910 0.560 ;
        RECT 39.750 0.270 40.290 0.560 ;
        RECT 41.130 0.270 41.670 0.560 ;
        RECT 42.510 0.270 43.050 0.560 ;
        RECT 43.890 0.270 44.430 0.560 ;
        RECT 45.270 0.270 45.810 0.560 ;
        RECT 46.650 0.270 47.190 0.560 ;
        RECT 48.030 0.270 48.570 0.560 ;
        RECT 49.410 0.270 49.950 0.560 ;
        RECT 50.790 0.270 51.330 0.560 ;
        RECT 52.170 0.270 52.710 0.560 ;
        RECT 53.550 0.270 54.090 0.560 ;
        RECT 54.930 0.270 55.470 0.560 ;
        RECT 56.310 0.270 56.850 0.560 ;
        RECT 57.690 0.270 58.230 0.560 ;
        RECT 59.070 0.270 59.610 0.560 ;
        RECT 60.450 0.270 60.990 0.560 ;
        RECT 61.830 0.270 62.370 0.560 ;
        RECT 63.210 0.270 63.750 0.560 ;
        RECT 64.590 0.270 65.130 0.560 ;
        RECT 65.970 0.270 66.510 0.560 ;
        RECT 67.350 0.270 67.890 0.560 ;
        RECT 68.730 0.270 69.270 0.560 ;
        RECT 70.110 0.270 70.650 0.560 ;
        RECT 71.490 0.270 72.030 0.560 ;
        RECT 72.870 0.270 73.410 0.560 ;
        RECT 74.250 0.270 74.790 0.560 ;
        RECT 75.630 0.270 76.170 0.560 ;
        RECT 77.010 0.270 77.550 0.560 ;
        RECT 78.390 0.270 78.930 0.560 ;
        RECT 79.770 0.270 80.310 0.560 ;
        RECT 81.150 0.270 81.690 0.560 ;
        RECT 82.530 0.270 83.070 0.560 ;
        RECT 83.910 0.270 84.450 0.560 ;
        RECT 85.290 0.270 85.830 0.560 ;
        RECT 86.670 0.270 87.210 0.560 ;
        RECT 88.050 0.270 88.590 0.560 ;
        RECT 89.430 0.270 89.970 0.560 ;
        RECT 90.810 0.270 91.350 0.560 ;
        RECT 92.190 0.270 92.730 0.560 ;
        RECT 93.570 0.270 94.110 0.560 ;
        RECT 94.950 0.270 95.490 0.560 ;
        RECT 96.330 0.270 96.870 0.560 ;
        RECT 97.710 0.270 98.250 0.560 ;
        RECT 99.090 0.270 99.630 0.560 ;
        RECT 100.470 0.270 101.010 0.560 ;
        RECT 101.850 0.270 102.390 0.560 ;
        RECT 103.230 0.270 103.770 0.560 ;
        RECT 104.610 0.270 105.150 0.560 ;
        RECT 105.990 0.270 106.530 0.560 ;
        RECT 107.370 0.270 107.910 0.560 ;
        RECT 108.750 0.270 109.290 0.560 ;
        RECT 110.130 0.270 110.670 0.560 ;
        RECT 111.510 0.270 112.050 0.560 ;
        RECT 112.890 0.270 113.430 0.560 ;
        RECT 114.270 0.270 114.810 0.560 ;
        RECT 115.650 0.270 116.190 0.560 ;
        RECT 117.030 0.270 117.570 0.560 ;
        RECT 118.410 0.270 118.950 0.560 ;
        RECT 119.790 0.270 120.330 0.560 ;
        RECT 121.170 0.270 121.710 0.560 ;
        RECT 122.550 0.270 123.090 0.560 ;
        RECT 123.930 0.270 124.470 0.560 ;
        RECT 125.310 0.270 125.850 0.560 ;
        RECT 126.690 0.270 127.230 0.560 ;
        RECT 128.070 0.270 128.610 0.560 ;
        RECT 129.450 0.270 129.990 0.560 ;
        RECT 130.830 0.270 131.370 0.560 ;
        RECT 132.210 0.270 132.750 0.560 ;
        RECT 133.590 0.270 134.130 0.560 ;
        RECT 134.970 0.270 135.510 0.560 ;
        RECT 136.350 0.270 136.890 0.560 ;
        RECT 137.730 0.270 138.270 0.560 ;
        RECT 139.110 0.270 139.650 0.560 ;
        RECT 140.490 0.270 141.030 0.560 ;
        RECT 141.870 0.270 142.410 0.560 ;
        RECT 143.250 0.270 143.790 0.560 ;
        RECT 144.630 0.270 145.170 0.560 ;
        RECT 146.010 0.270 146.550 0.560 ;
        RECT 147.390 0.270 147.930 0.560 ;
        RECT 148.770 0.270 149.310 0.560 ;
        RECT 150.150 0.270 150.690 0.560 ;
        RECT 151.530 0.270 152.070 0.560 ;
        RECT 152.910 0.270 153.450 0.560 ;
        RECT 154.290 0.270 154.830 0.560 ;
        RECT 155.670 0.270 156.210 0.560 ;
        RECT 157.050 0.270 157.590 0.560 ;
        RECT 158.430 0.270 158.970 0.560 ;
        RECT 159.810 0.270 160.350 0.560 ;
        RECT 161.190 0.270 161.730 0.560 ;
        RECT 162.570 0.270 163.110 0.560 ;
        RECT 163.950 0.270 164.490 0.560 ;
        RECT 165.330 0.270 165.870 0.560 ;
        RECT 166.710 0.270 167.250 0.560 ;
        RECT 168.090 0.270 168.630 0.560 ;
        RECT 169.470 0.270 170.010 0.560 ;
        RECT 170.850 0.270 171.390 0.560 ;
        RECT 172.230 0.270 172.770 0.560 ;
        RECT 173.610 0.270 174.150 0.560 ;
        RECT 174.990 0.270 175.530 0.560 ;
        RECT 176.370 0.270 176.910 0.560 ;
        RECT 177.750 0.270 178.290 0.560 ;
        RECT 179.130 0.270 179.670 0.560 ;
        RECT 180.510 0.270 181.050 0.560 ;
        RECT 181.890 0.270 182.430 0.560 ;
        RECT 183.270 0.270 183.810 0.560 ;
        RECT 184.650 0.270 185.190 0.560 ;
        RECT 186.030 0.270 186.570 0.560 ;
        RECT 187.410 0.270 187.950 0.560 ;
        RECT 188.790 0.270 189.330 0.560 ;
        RECT 190.170 0.270 190.710 0.560 ;
        RECT 191.550 0.270 192.090 0.560 ;
        RECT 192.930 0.270 193.470 0.560 ;
        RECT 194.310 0.270 194.850 0.560 ;
        RECT 195.690 0.270 196.230 0.560 ;
        RECT 197.070 0.270 197.610 0.560 ;
        RECT 198.450 0.270 217.950 0.560 ;
      LAYER met3 ;
        RECT 0.600 50.000 219.280 54.565 ;
        RECT 1.000 6.440 218.880 50.000 ;
        RECT 0.600 0.855 219.280 6.440 ;
  END
END N_term_MACC
END LIBRARY

